# written for xeda's tests
VERSION 5.8 ;
BUSBITCHARS "[]" ;
DIVIDERCHAR "/" ;

UNITS
  DATABASE MICRONS 1000 ;
END UNITS

MANUFACTURINGGRID 0.005 ;

PROPERTYDEFINITIONS
  LAYER LEF58_TYPE STRING ;
END PROPERTYDEFINITIONS

LAYER poly
  TYPE MASTERSLICE ;
END poly

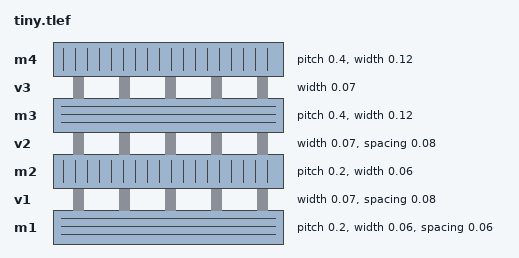
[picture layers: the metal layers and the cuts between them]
LAYER m1
  TYPE ROUTING ;
  DIRECTION HORIZONTAL ;
  PITCH 0.2 ;
  OFFSET 0.1 0.05 ;
  WIDTH 0.06 ;
  SPACING 0.06 ;
END m1

LAYER v1
  TYPE CUT ;
  SPACING 0.08 ;
  WIDTH 0.07 ;
END v1

LAYER m2
  TYPE ROUTING ;
  DIRECTION VERTICAL ;
  PITCH 0.2 0.3 ;
  OFFSET 0.1 0.15 ;
  WIDTH 0.06 ;
  SPACINGTABLE
    PARALLELRUNLENGTH 0.0 0.5
      WIDTH 0.0 0.06 0.06
      WIDTH 0.1 0.06 0.08 ;
END m2

LAYER v2
  TYPE CUT ;
  SPACING 0.08 ;
  WIDTH 0.07 ;
END v2

LAYER m3
  TYPE ROUTING ;
  DIRECTION HORIZONTAL ;
  PITCH 0.4 ;
  OFFSET 0.2 ;
  WIDTH 0.12 ;
END m3

LAYER v3
  TYPE CUT ;
  WIDTH 0.07 ;
END v3

LAYER m4
  TYPE ROUTING ;
  DIRECTION VERTICAL ;
  PITCH 0.4 ;
  WIDTH 0.12 ;
END m4

VIA v1_default DEFAULT
  LAYER m1 ;
    RECT -0.05 -0.05 0.05 0.05 ;
  LAYER v1 ;
    RECT -0.035 -0.035 0.035 0.035 ;
  LAYER m2 ;
    RECT -0.05 -0.05 0.05 0.05 ;
END v1_default

NONDEFAULTRULE wide
  LAYER m1
    WIDTH 0.12 ;
    SPACING 0.1 ;
    PITCH 0.6 ;
    OFFSET 0.3 ;
  END m1
END wide

SITE tinysite
  CLASS CORE ;
  SYMMETRY Y ;
  SIZE 0.2 BY 1.4 ;
END tinysite

SITE bigsite
  CLASS CORE ;
  SIZE 0.4 BY 2.8 ;
END bigsite

END LIBRARY
